VERSION 5.8 ;
BUSBITCHARS "[]" ;
DIVIDERCHAR "/" ;
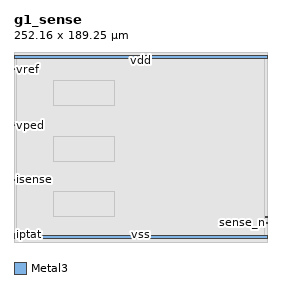
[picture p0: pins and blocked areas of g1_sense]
MACRO g1_sense
  CLASS BLOCK ;
  ORIGIN 0 0 ;
  FOREIGN g1_sense 0 0 ;
  SIZE 252.160 BY 189.250 ;
  SYMMETRY X Y ;
  PIN iptat
    DIRECTION INOUT ;
    USE SIGNAL ;
    PORT
      LAYER Metal3 ;
        RECT 0.000 7.000 2.000 8.000 ;
    END
  END iptat
  PIN isense
    DIRECTION INOUT ;
    USE SIGNAL ;
    PORT
      LAYER Metal3 ;
        RECT 0.000 61.700 2.000 62.700 ;
    END
  END isense
  PIN vped
    DIRECTION INOUT ;
    USE SIGNAL ;
    PORT
      LAYER Metal3 ;
        RECT 0.000 115.900 2.000 116.900 ;
    END
  END vped
  PIN vref_buf
    DIRECTION INOUT ;
    USE SIGNAL ;
    PORT
      LAYER Metal3 ;
        RECT 0.000 117.900 2.000 118.900 ;
    END
  END vref_buf
  PIN vref
    DIRECTION INOUT ;
    USE SIGNAL ;
    PORT
      LAYER Metal3 ;
        RECT 0.000 171.600 2.000 172.600 ;
    END
  END vref
  PIN sense_n
    DIRECTION INOUT ;
    USE SIGNAL ;
    PORT
      LAYER Metal3 ;
        RECT 250.160 18.500 252.160 19.500 ;
    END
  END sense_n
  PIN sense_p
    DIRECTION INOUT ;
    USE SIGNAL ;
    PORT
      LAYER Metal3 ;
        RECT 250.160 24.500 252.160 25.500 ;
    END
  END sense_p
  PIN vss
    DIRECTION INOUT ;
    USE GROUND ;
    PORT
      LAYER Metal3 ;
        RECT 0.000 3.000 252.160 6.000 ;
    END
  END vss
  PIN vdd
    DIRECTION INOUT ;
    USE POWER ;
    PORT
      LAYER Metal3 ;
        RECT 0.000 183.250 252.160 186.250 ;
    END
  END vdd
  OBS
    LAYER Metal1 ;
      RECT 0.000 0.000 252.160 189.250 ;
    LAYER Metal2 ;
      RECT 0.000 0.000 252.160 189.250 ;
    LAYER Metal3 ;
      RECT 2.500 6.500 249.660 182.750 ;
    LAYER Metal4 ;
      RECT 2.500 6.500 249.660 182.750 ;
    LAYER Metal5 ;
      RECT 2.500 6.500 249.660 182.750 ;
    LAYER TopMetal1 ;
      RECT 39.690 25.360 100.410 50.040 ;
    LAYER TopMetal1 ;
      RECT 39.690 80.560 100.410 105.240 ;
    LAYER TopMetal1 ;
      RECT 39.690 135.760 100.410 160.440 ;
  END
END g1_sense
END LIBRARY
